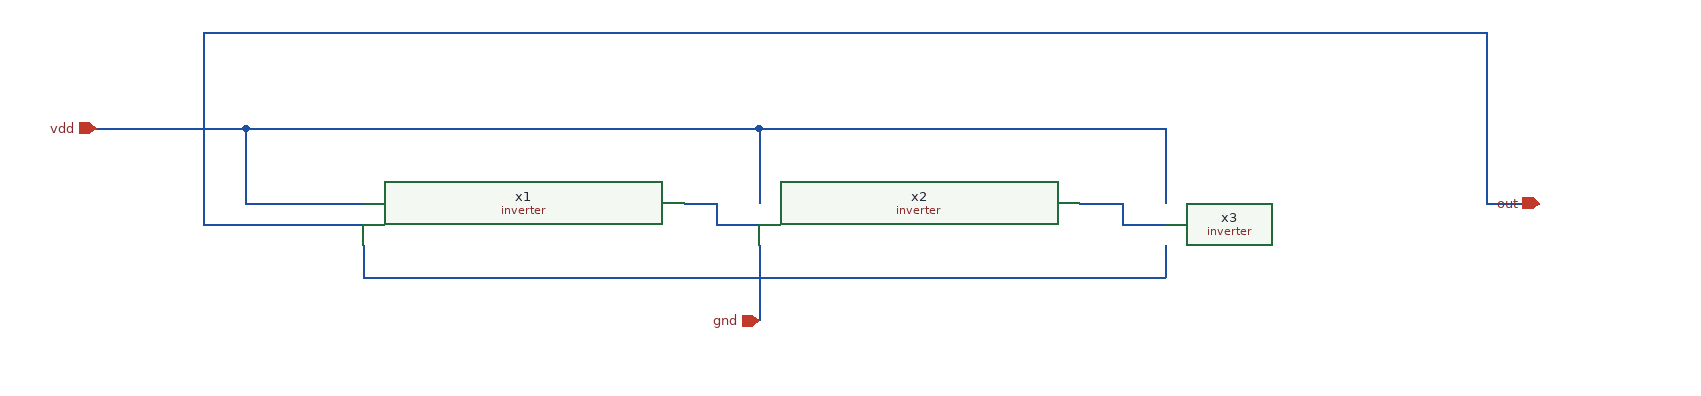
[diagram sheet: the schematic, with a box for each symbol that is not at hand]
v {xschem version=3.4.6RC file_version=1.2
}
G {}
K {}
V {}
S {}
E {}
N -480 -110 -370 -110 {lab=xxx}
N -480 -180 -480 -110 {lab=xxx}
N -480 -180 -0 -180 {lab=xxx}
N 0 -180 380 -180 {lab=xxx}
N 380 -180 380 -110 {lab=xxx}
N -370 -70 -370 -40 {lab=gnd}
N -370 -40 380 -40 {lab=gnd}
N 380 -70 380 -40 {lab=gnd}
N -0 -70 0 -40 {lab=gnd}
N 0 -40 0 -20 {lab=gnd}
N -520 -90 -370 -90 {lab=out}
N -70 -110 -40 -110 {lab=#net1}
N -40 -110 -40 -90 {lab=#net1}
N -40 -90 -0 -90 {lab=#net1}
N 300 -110 340 -110 {lab=#net2}
N 340 -110 340 -90 {lab=#net2}
N 340 -90 380 -90 {lab=#net2}
N 680 -270 680 -110 {lab=out}
N -520 -270 680 -270 {lab=out}
N -520 -270 -520 -90 {lab=out}
N 0 -180 0 -110 {lab=xxx}
N 0 -180 0 -110 {lab=xxx}
N -610 -180 -480 -180 {lab=xxx}
N 0 -10 0 -0 {lab=gnd}
N -0 -20 0 -10 {lab=gnd}
N -620 -180 -610 -180 {lab=xxx}
N 680 -110 730 -110 {lab=out}
C {/home/nsptrq/newproject/inverter/inverter.sym} -220 -90 0 0 {name=x1}
C {/home/nsptrq/newproject/inverter/inverter.sym} 150 -90 0 0 {name=x2}
C {/home/nsptrq/newproject/inverter/inverter.sym} 530 -90 0 0 {name=x3}
C {devices/iopin.sym} 730 -110 0 0 {name=p1 lab=out}
C {devices/iopin.sym} -620 -180 2 0 {name=p2 lab=vdd}
C {devices/iopin.sym} 0 0 1 0 {name=p3 lab=gnd}
